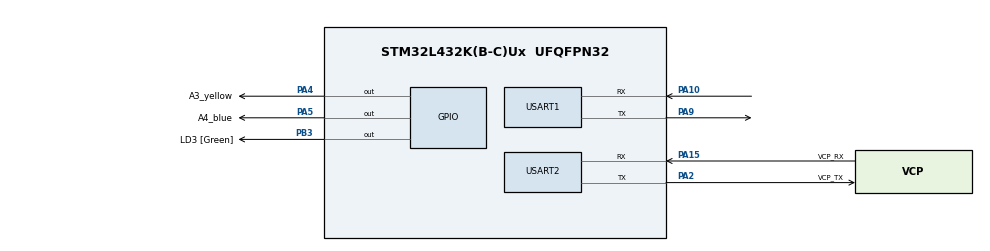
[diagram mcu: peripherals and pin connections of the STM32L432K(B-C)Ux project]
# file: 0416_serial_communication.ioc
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Dma.Request0=USART1_RX
Dma.USART1_RX.0.Direction=DMA_PERIPH_TO_MEMORY
Dma.USART1_RX.0.Instance=DMA1_Channel5
Dma.USART1_RX.0.MemDataAlignment=DMA_MDATAALIGN_BYTE
Dma.USART1_RX.0.MemInc=DMA_MINC_ENABLE
Dma.USART1_RX.0.Mode=DMA_NORMAL
Dma.USART1_RX.0.PeriphDataAlignment=DMA_PDATAALIGN_BYTE
Dma.USART1_RX.0.PeriphInc=DMA_PINC_DISABLE
Dma.USART1_RX.0.Priority=DMA_PRIORITY_LOW
Mcu.Family=STM32L4
Mcu.Name=STM32L432K(B-C)Ux
Mcu.Package=UFQFPN32
NVIC.DMA1_Channel5_IRQn=true\:0\:0\:false\:false\:true\:false\:true\:true
NVIC.PriorityGroup=NVIC_PRIORITYGROUP_4
NVIC.USART1_IRQn=true\:0\:0\:false\:false\:true\:true\:true\:true
NVIC.USART2_IRQn=true\:0\:0\:false\:false\:true\:true\:true\:true
PA0.GPIO_Label=MCO [High speed clock in]
PA0.Mode=HSE-External-Clock-Source-for-LittleOrca
PA0.Signal=RCC_CK_IN
PA10.Mode=Asynchronous
PA10.Signal=USART1_RX
PA13\ (JTMS-SWDIO).GPIO_Label=SWDIO
PA13\ (JTMS-SWDIO).Mode=Serial_Wire
PA13\ (JTMS-SWDIO).Signal=SYS_JTMS-SWDIO
PA14\ (JTCK-SWCLK).GPIO_Label=SWCLK
PA14\ (JTCK-SWCLK).Mode=Serial_Wire
PA14\ (JTCK-SWCLK).Signal=SYS_JTCK-SWCLK
PA15\ (JTDI).GPIO_Label=VCP_RX
PA15\ (JTDI).Mode=Asynchronous
PA15\ (JTDI).Signal=USART2_RX
PA2.GPIO_Label=VCP_TX
PA2.Mode=Asynchronous
PA2.Signal=USART2_TX
PA4.GPIO_Label=A3_yellow
PA4.Signal=GPIO_Output
PA5.GPIO_Label=A4_blue
PA5.Signal=GPIO_Output
PA9.Mode=Asynchronous
PA9.Signal=USART1_TX
PB3\ (JTDO-TRACESWO).GPIO_Label=LD3 [Green]
PB3\ (JTDO-TRACESWO).Signal=GPIO_Output
PC14-OSC32_IN\ (PC14).Mode=LSE-External-Oscillator
PC14-OSC32_IN\ (PC14).Signal=RCC_OSC32_IN
PC15-OSC32_OUT\ (PC15).Mode=LSE-External-Oscillator
PC15-OSC32_OUT\ (PC15).Signal=RCC_OSC32_OUT
ProjectManager.HeapSize=0x200
ProjectManager.StackSize=0x400
ProjectManager.TargetToolchain=STM32CubeIDE
RCC.AHBFreq_Value=80000000
RCC.APB1Freq_Value=80000000
RCC.APB1TimFreq_Value=80000000
RCC.APB2Freq_Value=80000000
RCC.APB2TimFreq_Value=80000000
RCC.CortexFreq_Value=80000000
RCC.HCLKFreq_Value=80000000
RCC.HSE_VALUE=8000000
RCC.HSI16_VALUE=16000000
RCC.HSI48_VALUE=48000000
RCC.HSI_VALUE=16000000
RCC.MSI_VALUE=4000000
RCC.PLLMUL=RCC_PLLMUL_4
RCC.PLLN=40
RCC.SYSCLKFreq_VALUE=80000000
RCC.SYSCLKSource=RCC_SYSCLKSOURCE_PLLCLK
RCC.VCOOutputFreq_Value=160000000
USART1.VirtualMode-Asynchronous=VM_ASYNC
USART2.VirtualMode-Asynchronous=VM_ASYNC
board=NUCLEO-L432KC

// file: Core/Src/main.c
/* USER CODE BEGIN Header */
/**
  ******************************************************************************
  * @file           : main.c
  * @brief          : Main program body
  ******************************************************************************
  * @attention
  *
  * Copyright (c) 2025 STMicroelectronics.
  * All rights reserved.
  *
  * This software is licensed under terms that can be found in the LICENSE file
  * in the root directory of this software component.
  * If no LICENSE file comes with this software, it is provided AS-IS.
  *
  ******************************************************************************
  */
/* USER CODE END Header */
#include "main.h"

/* USER CODE BEGIN Includes */
#include <string.h>
/* USER CODE END Includes */

UART_HandleTypeDef huart1;
UART_HandleTypeDef huart2;
DMA_HandleTypeDef hdma_usart1_rx;

/* USER CODE BEGIN PV */
char hello[] = "Initialize completed!";
uint8_t from_computer;
/* USER CODE END PV */

void SystemClock_Config(void);
static void MX_GPIO_Init(void);
static void MX_DMA_Init(void);
static void MX_USART2_UART_Init(void);
static void MX_USART1_UART_Init(void);

int main(void)
{

  /* USER CODE BEGIN 1 */
    HAL_Init();
    SystemClock_Config();
    MX_GPIO_Init();
    MX_USART2_UART_Init();
  /* USER CODE END 1 */

  /* MCU Configuration--------------------------------------------------------*/

  /* Reset of all peripherals, Initializes the Flash interface and the Systick. */
  HAL_Init();

  /* USER CODE BEGIN Init */
  // HAL_UART_Transmit(&huart2, (uint8_t)hello, sizeof(hello), 100); // 初始化訊息
  // HAL_UART_Receive_IT(&huart2, &from_computer, from_computer); // 接收電腦的訊息

  /* USER CODE END Init */

  /* Configure the system clock */
  SystemClock_Config();

  /* Initialize all configured peripherals */
  MX_GPIO_Init();
  MX_DMA_Init();
  MX_USART2_UART_Init();
  MX_USART1_UART_Init();
  /* USER CODE BEGIN 2 */
  HAL_UART_Receive_IT(&huart2, &from_computer, 1);

  /* USER CODE END 2 */

  /* Infinite loop */
  while (1)
  {
  }
}

void SystemClock_Config(void)
{
  RCC_OscInitTypeDef RCC_OscInitStruct = {0};
  RCC_ClkInitTypeDef RCC_ClkInitStruct = {0};

  /** Configure the main internal regulator output voltage
  */
  if (HAL_PWREx_ControlVoltageScaling(PWR_REGULATOR_VOLTAGE_SCALE1) != HAL_OK)
  {
    Error_Handler();
  }

  /** Configure LSE Drive Capability
  */
  HAL_PWR_EnableBkUpAccess();
  __HAL_RCC_LSEDRIVE_CONFIG(RCC_LSEDRIVE_LOW);

  /** Initializes the RCC Oscillators according to the specified parameters
  * in the RCC_OscInitTypeDef structure.
  */
  RCC_OscInitStruct.OscillatorType = RCC_OSCILLATORTYPE_LSE|RCC_OSCILLATORTYPE_MSI;
  RCC_OscInitStruct.LSEState = RCC_LSE_ON;
  RCC_OscInitStruct.MSIState = RCC_MSI_ON;
  RCC_OscInitStruct.MSICalibrationValue = 0;
  RCC_OscInitStruct.MSIClockRange = RCC_MSIRANGE_6;
  RCC_OscInitStruct.PLL.PLLState = RCC_PLL_ON;
  RCC_OscInitStruct.PLL.PLLSource = RCC_PLLSOURCE_MSI;
  RCC_OscInitStruct.PLL.PLLM = 1;
  RCC_OscInitStruct.PLL.PLLN = 16;
  RCC_OscInitStruct.PLL.PLLP = RCC_PLLP_DIV7;
  RCC_OscInitStruct.PLL.PLLQ = RCC_PLLQ_DIV2;
  RCC_OscInitStruct.PLL.PLLR = RCC_PLLR_DIV2;
  if (HAL_RCC_OscConfig(&RCC_OscInitStruct) != HAL_OK)
  {
    Error_Handler();
  }

  /** Initializes the CPU, AHB and APB buses clocks
  */
  RCC_ClkInitStruct.ClockType = RCC_CLOCKTYPE_HCLK|RCC_CLOCKTYPE_SYSCLK
                              |RCC_CLOCKTYPE_PCLK1|RCC_CLOCKTYPE_PCLK2;
  RCC_ClkInitStruct.SYSCLKSource = RCC_SYSCLKSOURCE_PLLCLK;
  RCC_ClkInitStruct.AHBCLKDivider = RCC_SYSCLK_DIV1;
  RCC_ClkInitStruct.APB1CLKDivider = RCC_HCLK_DIV1;
  RCC_ClkInitStruct.APB2CLKDivider = RCC_HCLK_DIV1;

  if (HAL_RCC_ClockConfig(&RCC_ClkInitStruct, FLASH_LATENCY_1) != HAL_OK)
  {
    Error_Handler();
  }

  /** Enable MSI Auto calibration
  */
  HAL_RCCEx_EnableMSIPLLMode();
}

static void MX_USART1_UART_Init(void)
{

  huart1.Instance = USART1;
  huart1.Init.BaudRate = 115200;
  huart1.Init.WordLength = UART_WORDLENGTH_8B;
  huart1.Init.StopBits = UART_STOPBITS_1;
  huart1.Init.Parity = UART_PARITY_NONE;
  huart1.Init.Mode = UART_MODE_TX_RX;
  huart1.Init.HwFlowCtl = UART_HWCONTROL_NONE;
  huart1.Init.OverSampling = UART_OVERSAMPLING_16;
  huart1.Init.OneBitSampling = UART_ONE_BIT_SAMPLE_DISABLE;
  huart1.AdvancedInit.AdvFeatureInit = UART_ADVFEATURE_NO_INIT;
  if (HAL_UART_Init(&huart1) != HAL_OK)
  {
    Error_Handler();
  }

}

static void MX_USART2_UART_Init(void)
{

  huart2.Instance = USART2;
  huart2.Init.BaudRate = 115200;
  huart2.Init.WordLength = UART_WORDLENGTH_8B;
  huart2.Init.StopBits = UART_STOPBITS_1;
  huart2.Init.Parity = UART_PARITY_NONE;
  huart2.Init.Mode = UART_MODE_TX_RX;
  huart2.Init.HwFlowCtl = UART_HWCONTROL_NONE;
  huart2.Init.OverSampling = UART_OVERSAMPLING_16;
  huart2.Init.OneBitSampling = UART_ONE_BIT_SAMPLE_DISABLE;
  huart2.AdvancedInit.AdvFeatureInit = UART_ADVFEATURE_NO_INIT;
  if (HAL_UART_Init(&huart2) != HAL_OK)
  {
    Error_Handler();
  }

}

static void MX_DMA_Init(void)
{

  /* DMA controller clock enable */
  __HAL_RCC_DMA1_CLK_ENABLE();

  /* DMA interrupt init */
  /* DMA1_Channel5_IRQn interrupt configuration */
  HAL_NVIC_SetPriority(DMA1_Channel5_IRQn, 0, 0);
  HAL_NVIC_EnableIRQ(DMA1_Channel5_IRQn);

}

static void MX_GPIO_Init(void)
{
  GPIO_InitTypeDef GPIO_InitStruct = {0};

  /* GPIO Ports Clock Enable */
  __HAL_RCC_GPIOC_CLK_ENABLE();
  __HAL_RCC_GPIOA_CLK_ENABLE();
  __HAL_RCC_GPIOB_CLK_ENABLE();

  /*Configure GPIO pin Output Level */
  HAL_GPIO_WritePin(GPIOA, A3_yellow_Pin|A4_blue_Pin, GPIO_PIN_RESET);

  /*Configure GPIO pin Output Level */
  HAL_GPIO_WritePin(LD3_GPIO_Port, LD3_Pin, GPIO_PIN_RESET);

  /*Configure GPIO pins : A3_yellow_Pin A4_blue_Pin */
  GPIO_InitStruct.Pin = A3_yellow_Pin|A4_blue_Pin;
  GPIO_InitStruct.Mode = GPIO_MODE_OUTPUT_PP;
  GPIO_InitStruct.Pull = GPIO_NOPULL;
  GPIO_InitStruct.Speed = GPIO_SPEED_FREQ_LOW;
  HAL_GPIO_Init(GPIOA, &GPIO_InitStruct);

  /*Configure GPIO pin : LD3_Pin */
  GPIO_InitStruct.Pin = LD3_Pin;
  GPIO_InitStruct.Mode = GPIO_MODE_OUTPUT_PP;
  GPIO_InitStruct.Pull = GPIO_NOPULL;
  GPIO_InitStruct.Speed = GPIO_SPEED_FREQ_LOW;
  HAL_GPIO_Init(LD3_GPIO_Port, &GPIO_InitStruct);

}

/* USER CODE BEGIN 4 */
    // 在stm32l4xx_it.c裡面的IR甚麼東西對著他ctrl點擊
    void HAL_UART_RxCpltCallback(UART_HandleTypeDef *huart){
    	  UNUSED(huart);
    	  if(from_computer == '1'){
    		  HAL_GPIO_TogglePin(A4_blue_GPIO_Port, A4_blue_Pin);
    	  }
    	  // 重新啟動下一個中斷
    	  HAL_UART_Receive_IT(&huart2, &from_computer, 1);
    }

/* USER CODE END 4 */

void Error_Handler(void)
{
  __disable_irq();
  while (1)
  {
  }
}
